VERSION 5.7 ;
  NOWIREEXTENSIONATPIN ON ;
  DIVIDERCHAR "/" ;
  BUSBITCHARS "[]" ;
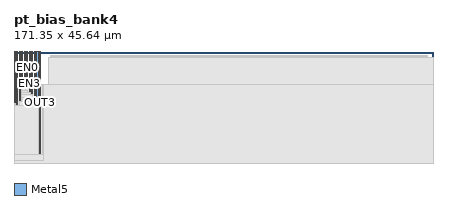
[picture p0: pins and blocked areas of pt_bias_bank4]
MACRO pt_bias_bank4
  CLASS BLOCK ;
  FOREIGN pt_bias_bank4 ;
  ORIGIN -0.300 44.420 ;
  SIZE 171.350 BY 45.640 ;
  PIN VDD
    DIRECTION INOUT ;
    USE POWER ;
    PORT
      LAYER Metal5 ;
        RECT 0.300 -19.620 0.740 1.220 ;
    END
  END VDD
  PIN VSS
    DIRECTION INOUT ;
    USE GROUND ;
    PORT
      LAYER Metal5 ;
        RECT 1.340 -20.520 1.780 1.220 ;
    END
  END VSS
  PIN TRK
    DIRECTION INPUT ;
    USE SIGNAL ;
    ANTENNAGATEAREA 200.000000 ;
    ANTENNADIFFAREA 2.600000 ;
    PORT
      LAYER Metal5 ;
        RECT 2.380 -18.720 2.820 1.220 ;
    END
  END TRK
  PIN EN0
    DIRECTION INPUT ;
    USE SIGNAL ;
    ANTENNAGATEAREA 3.360000 ;
    PORT
      LAYER Metal5 ;
        RECT 3.420 -12.420 3.860 1.220 ;
    END
  END EN0
  PIN EN1
    DIRECTION INPUT ;
    USE SIGNAL ;
    ANTENNAGATEAREA 3.360000 ;
    PORT
      LAYER Metal5 ;
        RECT 4.460 -13.320 4.900 1.220 ;
    END
  END EN1
  PIN EN2
    DIRECTION INPUT ;
    USE SIGNAL ;
    ANTENNAGATEAREA 3.360000 ;
    PORT
      LAYER Metal5 ;
        RECT 5.500 -14.220 5.940 1.220 ;
    END
  END EN2
  PIN EN3
    DIRECTION INPUT ;
    USE SIGNAL ;
    ANTENNAGATEAREA 3.360000 ;
    PORT
      LAYER Metal5 ;
        RECT 6.540 -15.120 6.980 1.220 ;
    END
  END EN3
  PIN OUT0
    DIRECTION OUTPUT ;
    USE SIGNAL ;
    ANTENNADIFFAREA 3.520000 ;
    PORT
      LAYER Metal5 ;
        RECT 7.580 -16.020 8.020 1.220 ;
    END
  END OUT0
  PIN OUT1
    DIRECTION OUTPUT ;
    USE SIGNAL ;
    ANTENNADIFFAREA 3.520000 ;
    PORT
      LAYER Metal5 ;
        RECT 8.620 -16.920 9.060 1.220 ;
    END
  END OUT1
  PIN OUT2
    DIRECTION OUTPUT ;
    USE SIGNAL ;
    ANTENNADIFFAREA 3.520000 ;
    PORT
      LAYER Metal5 ;
        RECT 9.660 -17.820 10.100 1.220 ;
    END
  END OUT2
  PIN OUT3
    DIRECTION OUTPUT ;
    USE SIGNAL ;
    ANTENNADIFFAREA 3.520000 ;
    PORT
      LAYER Metal5 ;
        RECT 10.700 -40.480 11.140 1.220 ;
    END
  END OUT3
  OBS
      LAYER Nwell ;
        RECT 15.330 -39.220 169.050 -0.600 ;
      LAYER Metal1 ;
        RECT 15.515 -39.120 168.950 -0.785 ;
      LAYER Metal2 ;
        RECT 14.430 -39.120 171.650 -1.360 ;
      LAYER Metal3 ;
        RECT 14.430 -44.420 171.650 -1.360 ;
      LAYER Metal4 ;
        RECT 0.320 -44.420 171.650 -12.360 ;
      LAYER Metal5 ;
        RECT 3.420 -13.920 3.860 -13.020 ;
        RECT 3.420 -14.820 4.900 -13.920 ;
        RECT 3.420 -15.720 5.940 -14.820 ;
        RECT 3.420 -16.620 6.980 -15.720 ;
        RECT 3.420 -17.520 8.020 -16.620 ;
        RECT 3.420 -18.420 9.060 -17.520 ;
        RECT 3.420 -19.320 10.100 -18.420 ;
        RECT 0.300 -19.900 0.380 -19.620 ;
        RECT 0.300 -21.120 0.740 -19.900 ;
        RECT 2.380 -21.120 10.100 -19.320 ;
        RECT 0.300 -41.080 10.100 -21.120 ;
        RECT 11.740 -41.080 12.180 -12.420 ;
        RECT 0.300 -43.540 12.180 -41.080 ;
  END
END pt_bias_bank4
END LIBRARY

